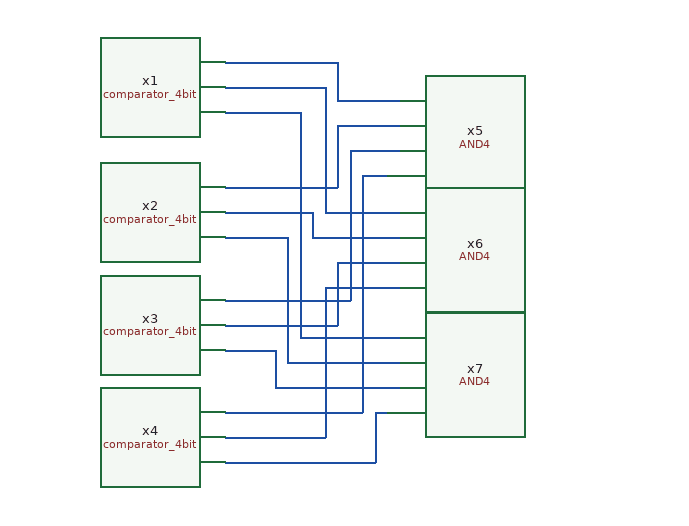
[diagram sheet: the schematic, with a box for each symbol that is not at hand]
v {xschem version=3.4.5 file_version=1.2
}
G {}
K {}
V {}
S {}
E {}
N 520 -850 610 -850 {
lab=#net1}
N 610 -850 610 -820 {
lab=#net1}
N 610 -820 660 -820 {
lab=#net1}
N 520 -750 610 -750 {
lab=#net2}
N 610 -800 610 -750 {
lab=#net2}
N 610 -800 660 -800 {
lab=#net2}
N 520 -660 620 -660 {
lab=#net3}
N 620 -780 620 -660 {
lab=#net3}
N 620 -780 660 -780 {
lab=#net3}
N 630 -760 650 -760 {
lab=#net4}
N 630 -760 630 -570 {
lab=#net4}
N 520 -570 630 -570 {
lab=#net4}
N 520 -830 590 -830 {
lab=#net5}
N 590 -830 600 -830 {
lab=#net5}
N 600 -830 600 -730 {
lab=#net5}
N 600 -730 660 -730 {
lab=#net5}
N 520 -730 590 -730 {
lab=#net6}
N 590 -730 590 -710 {
lab=#net6}
N 590 -710 660 -710 {
lab=#net6}
N 520 -640 610 -640 {
lab=#net7}
N 610 -690 610 -640 {
lab=#net7}
N 610 -690 660 -690 {
lab=#net7}
N 520 -550 600 -550 {
lab=#net8}
N 600 -670 600 -550 {
lab=#net8}
N 600 -670 660 -670 {
lab=#net8}
N 520 -810 580 -810 {
lab=#net9}
N 580 -810 580 -630 {
lab=#net9}
N 580 -630 650 -630 {
lab=#net9}
N 650 -630 660 -630 {
lab=#net9}
N 520 -530 640 -530 {
lab=#net10}
N 640 -570 640 -530 {
lab=#net10}
N 640 -570 650 -570 {
lab=#net10}
N 520 -710 570 -710 {
lab=#net11}
N 570 -710 570 -610 {
lab=#net11}
N 570 -610 660 -610 {
lab=#net11}
N 520 -620 560 -620 {
lab=#net12}
N 560 -620 560 -590 {
lab=#net12}
N 560 -590 660 -590 {
lab=#net12}
C {comparator_4bit.sym} 430 -830 0 0 {name=x1}
C {comparator_4bit.sym} 430 -730 0 0 {name=x2}
C {comparator_4bit.sym} 430 -640 0 0 {name=x3}
C {comparator_4bit.sym} 430 -550 0 0 {name=x4}
C {AND4.sym} 741 -789 0 0 {name=x5}
C {AND4.sym} 740 -699 0 0 {name=x6}
C {AND4.sym} 740 -599 0 0 {name=x7}
